##
## LEF for PtnCells ;
## created by Innovus v17.13-s098_1 on Sat Dec  7 00:01:32 2019
##

VERSION 5.8 ;

BUSBITCHARS "[]" ;
DIVIDERCHAR "/" ;

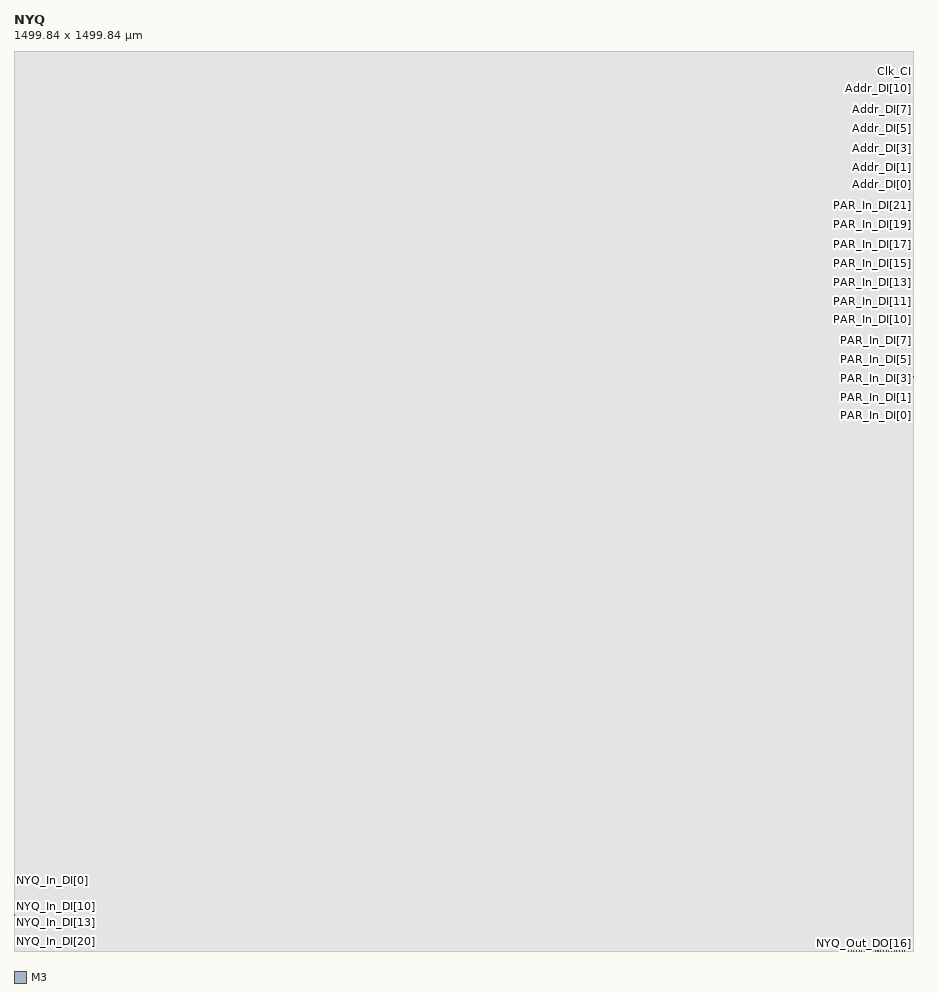
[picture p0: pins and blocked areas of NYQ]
MACRO NYQ
  CLASS BLOCK ;
  SIZE 1499.8400 BY 1499.8400 ;
  FOREIGN NYQ 0.0000 0.0000 ;
  ORIGIN 0 0 ;
  SYMMETRY X Y R90 ;
  PIN Clk_CI
    DIRECTION INPUT ;
    USE SIGNAL ;
    PORT
      LAYER M3 ;
        RECT 1499.6800 1452.5600 1499.8400 1452.7200 ;
    END
  END Clk_CI
  PIN Rst_RBI
    DIRECTION INPUT ;
    USE SIGNAL ;
    PORT
      LAYER M3 ;
        RECT 1499.6800 1468.5600 1499.8400 1468.7200 ;
    END
  END Rst_RBI
  PIN WrEn_SI
    DIRECTION INPUT ;
    USE SIGNAL ;
    PORT
      LAYER M3 ;
        RECT 1499.6800 1484.5600 1499.8400 1484.7200 ;
    END
  END WrEn_SI
  PIN Addr_DI[10]
    DIRECTION INPUT ;
    USE SIGNAL ;
    PORT
      LAYER M3 ;
        RECT 1499.6800 1436.5600 1499.8400 1436.7200 ;
    END
  END Addr_DI[10]
  PIN Addr_DI[9]
    DIRECTION INPUT ;
    USE SIGNAL ;
    PORT
      LAYER M3 ;
        RECT 1499.6800 1420.5600 1499.8400 1420.7200 ;
    END
  END Addr_DI[9]
  PIN Addr_DI[8]
    DIRECTION INPUT ;
    USE SIGNAL ;
    PORT
      LAYER M3 ;
        RECT 1499.6800 1404.5600 1499.8400 1404.7200 ;
    END
  END Addr_DI[8]
  PIN Addr_DI[7]
    DIRECTION INPUT ;
    USE SIGNAL ;
    PORT
      LAYER M3 ;
        RECT 1499.6800 1388.5600 1499.8400 1388.7200 ;
    END
  END Addr_DI[7]
  PIN Addr_DI[6]
    DIRECTION INPUT ;
    USE SIGNAL ;
    PORT
      LAYER M3 ;
        RECT 1499.6800 1372.5600 1499.8400 1372.7200 ;
    END
  END Addr_DI[6]
  PIN Addr_DI[5]
    DIRECTION INPUT ;
    USE SIGNAL ;
    PORT
      LAYER M3 ;
        RECT 1499.6800 1356.5600 1499.8400 1356.7200 ;
    END
  END Addr_DI[5]
  PIN Addr_DI[4]
    DIRECTION INPUT ;
    USE SIGNAL ;
    PORT
      LAYER M3 ;
        RECT 1499.6800 1340.5600 1499.8400 1340.7200 ;
    END
  END Addr_DI[4]
  PIN Addr_DI[3]
    DIRECTION INPUT ;
    USE SIGNAL ;
    PORT
      LAYER M3 ;
        RECT 1499.6800 1324.5600 1499.8400 1324.7200 ;
    END
  END Addr_DI[3]
  PIN Addr_DI[2]
    DIRECTION INPUT ;
    USE SIGNAL ;
    PORT
      LAYER M3 ;
        RECT 1499.6800 1308.5600 1499.8400 1308.7200 ;
    END
  END Addr_DI[2]
  PIN Addr_DI[1]
    DIRECTION INPUT ;
    USE SIGNAL ;
    PORT
      LAYER M3 ;
        RECT 1499.6800 1292.5600 1499.8400 1292.7200 ;
    END
  END Addr_DI[1]
  PIN Addr_DI[0]
    DIRECTION INPUT ;
    USE SIGNAL ;
    PORT
      LAYER M3 ;
        RECT 1499.6800 1276.5600 1499.8400 1276.7200 ;
    END
  END Addr_DI[0]
  PIN PAR_In_DI[23]
    DIRECTION INPUT ;
    USE SIGNAL ;
    PORT
      LAYER M3 ;
        RECT 1499.6800 1260.5600 1499.8400 1260.7200 ;
    END
  END PAR_In_DI[23]
  PIN PAR_In_DI[22]
    DIRECTION INPUT ;
    USE SIGNAL ;
    PORT
      LAYER M3 ;
        RECT 1499.6800 1244.5600 1499.8400 1244.7200 ;
    END
  END PAR_In_DI[22]
  PIN PAR_In_DI[21]
    DIRECTION INPUT ;
    USE SIGNAL ;
    PORT
      LAYER M3 ;
        RECT 1499.6800 1228.5600 1499.8400 1228.7200 ;
    END
  END PAR_In_DI[21]
  PIN PAR_In_DI[20]
    DIRECTION INPUT ;
    USE SIGNAL ;
    PORT
      LAYER M3 ;
        RECT 1499.6800 1212.5600 1499.8400 1212.7200 ;
    END
  END PAR_In_DI[20]
  PIN PAR_In_DI[19]
    DIRECTION INPUT ;
    USE SIGNAL ;
    PORT
      LAYER M3 ;
        RECT 1499.6800 1196.5600 1499.8400 1196.7200 ;
    END
  END PAR_In_DI[19]
  PIN PAR_In_DI[18]
    DIRECTION INPUT ;
    USE SIGNAL ;
    PORT
      LAYER M3 ;
        RECT 1499.6800 1180.5600 1499.8400 1180.7200 ;
    END
  END PAR_In_DI[18]
  PIN PAR_In_DI[17]
    DIRECTION INPUT ;
    USE SIGNAL ;
    PORT
      LAYER M3 ;
        RECT 1499.6800 1164.5600 1499.8400 1164.7200 ;
    END
  END PAR_In_DI[17]
  PIN PAR_In_DI[16]
    DIRECTION INPUT ;
    USE SIGNAL ;
    PORT
      LAYER M3 ;
        RECT 1499.6800 1148.5600 1499.8400 1148.7200 ;
    END
  END PAR_In_DI[16]
  PIN PAR_In_DI[15]
    DIRECTION INPUT ;
    USE SIGNAL ;
    PORT
      LAYER M3 ;
        RECT 1499.6800 1132.5600 1499.8400 1132.7200 ;
    END
  END PAR_In_DI[15]
  PIN PAR_In_DI[14]
    DIRECTION INPUT ;
    USE SIGNAL ;
    PORT
      LAYER M3 ;
        RECT 1499.6800 1116.5600 1499.8400 1116.7200 ;
    END
  END PAR_In_DI[14]
  PIN PAR_In_DI[13]
    DIRECTION INPUT ;
    USE SIGNAL ;
    PORT
      LAYER M3 ;
        RECT 1499.6800 1100.5600 1499.8400 1100.7200 ;
    END
  END PAR_In_DI[13]
  PIN PAR_In_DI[12]
    DIRECTION INPUT ;
    USE SIGNAL ;
    PORT
      LAYER M3 ;
        RECT 1499.6800 1084.5600 1499.8400 1084.7200 ;
    END
  END PAR_In_DI[12]
  PIN PAR_In_DI[11]
    DIRECTION INPUT ;
    USE SIGNAL ;
    PORT
      LAYER M3 ;
        RECT 1499.6800 1068.5600 1499.8400 1068.7200 ;
    END
  END PAR_In_DI[11]
  PIN PAR_In_DI[10]
    DIRECTION INPUT ;
    USE SIGNAL ;
    PORT
      LAYER M3 ;
        RECT 1499.6800 1052.5600 1499.8400 1052.7200 ;
    END
  END PAR_In_DI[10]
  PIN PAR_In_DI[9]
    DIRECTION INPUT ;
    USE SIGNAL ;
    PORT
      LAYER M3 ;
        RECT 1499.6800 1036.5600 1499.8400 1036.7200 ;
    END
  END PAR_In_DI[9]
  PIN PAR_In_DI[8]
    DIRECTION INPUT ;
    USE SIGNAL ;
    PORT
      LAYER M3 ;
        RECT 1499.6800 1020.5600 1499.8400 1020.7200 ;
    END
  END PAR_In_DI[8]
  PIN PAR_In_DI[7]
    DIRECTION INPUT ;
    USE SIGNAL ;
    PORT
      LAYER M3 ;
        RECT 1499.6800 1004.5600 1499.8400 1004.7200 ;
    END
  END PAR_In_DI[7]
  PIN PAR_In_DI[6]
    DIRECTION INPUT ;
    USE SIGNAL ;
    PORT
      LAYER M3 ;
        RECT 1499.6800 988.5600 1499.8400 988.7200 ;
    END
  END PAR_In_DI[6]
  PIN PAR_In_DI[5]
    DIRECTION INPUT ;
    USE SIGNAL ;
    PORT
      LAYER M3 ;
        RECT 1499.6800 972.5600 1499.8400 972.7200 ;
    END
  END PAR_In_DI[5]
  PIN PAR_In_DI[4]
    DIRECTION INPUT ;
    USE SIGNAL ;
    PORT
      LAYER M3 ;
        RECT 1499.6800 956.5600 1499.8400 956.7200 ;
    END
  END PAR_In_DI[4]
  PIN PAR_In_DI[3]
    DIRECTION INPUT ;
    USE SIGNAL ;
    PORT
      LAYER M3 ;
        RECT 1499.6800 940.5600 1499.8400 940.7200 ;
    END
  END PAR_In_DI[3]
  PIN PAR_In_DI[2]
    DIRECTION INPUT ;
    USE SIGNAL ;
    PORT
      LAYER M3 ;
        RECT 1499.6800 924.5600 1499.8400 924.7200 ;
    END
  END PAR_In_DI[2]
  PIN PAR_In_DI[1]
    DIRECTION INPUT ;
    USE SIGNAL ;
    PORT
      LAYER M3 ;
        RECT 1499.6800 908.5600 1499.8400 908.7200 ;
    END
  END PAR_In_DI[1]
  PIN PAR_In_DI[0]
    DIRECTION INPUT ;
    USE SIGNAL ;
    PORT
      LAYER M3 ;
        RECT 1499.6800 892.5600 1499.8400 892.7200 ;
    END
  END PAR_In_DI[0]
  PIN NYQ_In_DI[23]
    DIRECTION INPUT ;
    USE SIGNAL ;
    PORT
      LAYER M3 ;
        RECT 0.0000 15.1200 0.1600 15.2800 ;
    END
  END NYQ_In_DI[23]
  PIN NYQ_In_DI[22]
    DIRECTION INPUT ;
    USE SIGNAL ;
    PORT
      LAYER M3 ;
        RECT 0.0000 19.6000 0.1600 19.7600 ;
    END
  END NYQ_In_DI[22]
  PIN NYQ_In_DI[21]
    DIRECTION INPUT ;
    USE SIGNAL ;
    PORT
      LAYER M3 ;
        RECT 0.0000 24.0800 0.1600 24.2400 ;
    END
  END NYQ_In_DI[21]
  PIN NYQ_In_DI[20]
    DIRECTION INPUT ;
    USE SIGNAL ;
    PORT
      LAYER M3 ;
        RECT 0.0000 28.5600 0.1600 28.7200 ;
    END
  END NYQ_In_DI[20]
  PIN NYQ_In_DI[19]
    DIRECTION INPUT ;
    USE SIGNAL ;
    PORT
      LAYER M3 ;
        RECT 0.0000 33.0400 0.1600 33.2000 ;
    END
  END NYQ_In_DI[19]
  PIN NYQ_In_DI[18]
    DIRECTION INPUT ;
    USE SIGNAL ;
    PORT
      LAYER M3 ;
        RECT 0.0000 37.5200 0.1600 37.6800 ;
    END
  END NYQ_In_DI[18]
  PIN NYQ_In_DI[17]
    DIRECTION INPUT ;
    USE SIGNAL ;
    PORT
      LAYER M3 ;
        RECT 0.0000 42.0000 0.1600 42.1600 ;
    END
  END NYQ_In_DI[17]
  PIN NYQ_In_DI[16]
    DIRECTION INPUT ;
    USE SIGNAL ;
    PORT
      LAYER M3 ;
        RECT 0.0000 46.4800 0.1600 46.6400 ;
    END
  END NYQ_In_DI[16]
  PIN NYQ_In_DI[15]
    DIRECTION INPUT ;
    USE SIGNAL ;
    PORT
      LAYER M3 ;
        RECT 0.0000 50.9600 0.1600 51.1200 ;
    END
  END NYQ_In_DI[15]
  PIN NYQ_In_DI[14]
    DIRECTION INPUT ;
    USE SIGNAL ;
    PORT
      LAYER M3 ;
        RECT 0.0000 55.4400 0.1600 55.6000 ;
    END
  END NYQ_In_DI[14]
  PIN NYQ_In_DI[13]
    DIRECTION INPUT ;
    USE SIGNAL ;
    PORT
      LAYER M3 ;
        RECT 0.0000 59.9200 0.1600 60.0800 ;
    END
  END NYQ_In_DI[13]
  PIN NYQ_In_DI[12]
    DIRECTION INPUT ;
    USE SIGNAL ;
    PORT
      LAYER M3 ;
        RECT 0.0000 64.4000 0.1600 64.5600 ;
    END
  END NYQ_In_DI[12]
  PIN NYQ_In_DI[11]
    DIRECTION INPUT ;
    USE SIGNAL ;
    PORT
      LAYER M3 ;
        RECT 0.0000 68.8800 0.1600 69.0400 ;
    END
  END NYQ_In_DI[11]
  PIN NYQ_In_DI[10]
    DIRECTION INPUT ;
    USE SIGNAL ;
    PORT
      LAYER M3 ;
        RECT 0.0000 73.3600 0.1600 73.5200 ;
    END
  END NYQ_In_DI[10]
  PIN NYQ_In_DI[9]
    DIRECTION INPUT ;
    USE SIGNAL ;
    PORT
      LAYER M3 ;
        RECT 0.0000 77.8400 0.1600 78.0000 ;
    END
  END NYQ_In_DI[9]
  PIN NYQ_In_DI[8]
    DIRECTION INPUT ;
    USE SIGNAL ;
    PORT
      LAYER M3 ;
        RECT 0.0000 82.3200 0.1600 82.4800 ;
    END
  END NYQ_In_DI[8]
  PIN NYQ_In_DI[7]
    DIRECTION INPUT ;
    USE SIGNAL ;
    PORT
      LAYER M3 ;
        RECT 0.0000 86.8000 0.1600 86.9600 ;
    END
  END NYQ_In_DI[7]
  PIN NYQ_In_DI[6]
    DIRECTION INPUT ;
    USE SIGNAL ;
    PORT
      LAYER M3 ;
        RECT 0.0000 91.2800 0.1600 91.4400 ;
    END
  END NYQ_In_DI[6]
  PIN NYQ_In_DI[5]
    DIRECTION INPUT ;
    USE SIGNAL ;
    PORT
      LAYER M3 ;
        RECT 0.0000 95.7600 0.1600 95.9200 ;
    END
  END NYQ_In_DI[5]
  PIN NYQ_In_DI[4]
    DIRECTION INPUT ;
    USE SIGNAL ;
    PORT
      LAYER M3 ;
        RECT 0.0000 100.2400 0.1600 100.4000 ;
    END
  END NYQ_In_DI[4]
  PIN NYQ_In_DI[3]
    DIRECTION INPUT ;
    USE SIGNAL ;
    PORT
      LAYER M3 ;
        RECT 0.0000 104.7200 0.1600 104.8800 ;
    END
  END NYQ_In_DI[3]
  PIN NYQ_In_DI[2]
    DIRECTION INPUT ;
    USE SIGNAL ;
    PORT
      LAYER M3 ;
        RECT 0.0000 109.2000 0.1600 109.3600 ;
    END
  END NYQ_In_DI[2]
  PIN NYQ_In_DI[1]
    DIRECTION INPUT ;
    USE SIGNAL ;
    PORT
      LAYER M3 ;
        RECT 0.0000 113.6800 0.1600 113.8400 ;
    END
  END NYQ_In_DI[1]
  PIN NYQ_In_DI[0]
    DIRECTION INPUT ;
    USE SIGNAL ;
    PORT
      LAYER M3 ;
        RECT 0.0000 118.1600 0.1600 118.3200 ;
    END
  END NYQ_In_DI[0]
  PIN NYQ_Out_DO[23]
    DIRECTION OUTPUT ;
    USE SIGNAL ;
    PORT
      LAYER M3 ;
        RECT 1484.5600 0.0000 1484.7200 0.1600 ;
    END
  END NYQ_Out_DO[23]
  PIN NYQ_Out_DO[22]
    DIRECTION OUTPUT ;
    USE SIGNAL ;
    PORT
      LAYER M3 ;
        RECT 1480.0800 0.0000 1480.2400 0.1600 ;
    END
  END NYQ_Out_DO[22]
  PIN NYQ_Out_DO[21]
    DIRECTION OUTPUT ;
    USE SIGNAL ;
    PORT
      LAYER M3 ;
        RECT 1475.6000 0.0000 1475.7600 0.1600 ;
    END
  END NYQ_Out_DO[21]
  PIN NYQ_Out_DO[20]
    DIRECTION OUTPUT ;
    USE SIGNAL ;
    PORT
      LAYER M3 ;
        RECT 1471.1200 0.0000 1471.2800 0.1600 ;
    END
  END NYQ_Out_DO[20]
  PIN NYQ_Out_DO[19]
    DIRECTION OUTPUT ;
    USE SIGNAL ;
    PORT
      LAYER M3 ;
        RECT 1466.6400 0.0000 1466.8000 0.1600 ;
    END
  END NYQ_Out_DO[19]
  PIN NYQ_Out_DO[18]
    DIRECTION OUTPUT ;
    USE SIGNAL ;
    PORT
      LAYER M3 ;
        RECT 1462.1600 0.0000 1462.3200 0.1600 ;
    END
  END NYQ_Out_DO[18]
  PIN NYQ_Out_DO[17]
    DIRECTION OUTPUT ;
    USE SIGNAL ;
    PORT
      LAYER M3 ;
        RECT 1457.6800 0.0000 1457.8400 0.1600 ;
    END
  END NYQ_Out_DO[17]
  PIN NYQ_Out_DO[16]
    DIRECTION OUTPUT ;
    USE SIGNAL ;
    PORT
      LAYER M3 ;
        RECT 1453.2000 0.0000 1453.3600 0.1600 ;
    END
  END NYQ_Out_DO[16]
  PIN NYQ_Out_DO[15]
    DIRECTION OUTPUT ;
    USE SIGNAL ;
    PORT
      LAYER M3 ;
        RECT 1448.7200 0.0000 1448.8800 0.1600 ;
    END
  END NYQ_Out_DO[15]
  PIN NYQ_Out_DO[14]
    DIRECTION OUTPUT ;
    USE SIGNAL ;
    PORT
      LAYER M3 ;
        RECT 1444.2400 0.0000 1444.4000 0.1600 ;
    END
  END NYQ_Out_DO[14]
  PIN NYQ_Out_DO[13]
    DIRECTION OUTPUT ;
    USE SIGNAL ;
    PORT
      LAYER M3 ;
        RECT 1439.7600 0.0000 1439.9200 0.1600 ;
    END
  END NYQ_Out_DO[13]
  PIN NYQ_Out_DO[12]
    DIRECTION OUTPUT ;
    USE SIGNAL ;
    PORT
      LAYER M3 ;
        RECT 1435.2800 0.0000 1435.4400 0.1600 ;
    END
  END NYQ_Out_DO[12]
  PIN NYQ_Out_DO[11]
    DIRECTION OUTPUT ;
    USE SIGNAL ;
    PORT
      LAYER M3 ;
        RECT 1430.8000 0.0000 1430.9600 0.1600 ;
    END
  END NYQ_Out_DO[11]
  PIN NYQ_Out_DO[10]
    DIRECTION OUTPUT ;
    USE SIGNAL ;
    PORT
      LAYER M3 ;
        RECT 1426.3200 0.0000 1426.4800 0.1600 ;
    END
  END NYQ_Out_DO[10]
  PIN NYQ_Out_DO[9]
    DIRECTION OUTPUT ;
    USE SIGNAL ;
    PORT
      LAYER M3 ;
        RECT 1421.8400 0.0000 1422.0000 0.1600 ;
    END
  END NYQ_Out_DO[9]
  PIN NYQ_Out_DO[8]
    DIRECTION OUTPUT ;
    USE SIGNAL ;
    PORT
      LAYER M3 ;
        RECT 1417.3600 0.0000 1417.5200 0.1600 ;
    END
  END NYQ_Out_DO[8]
  PIN NYQ_Out_DO[7]
    DIRECTION OUTPUT ;
    USE SIGNAL ;
    PORT
      LAYER M3 ;
        RECT 1412.8800 0.0000 1413.0400 0.1600 ;
    END
  END NYQ_Out_DO[7]
  PIN NYQ_Out_DO[6]
    DIRECTION OUTPUT ;
    USE SIGNAL ;
    PORT
      LAYER M3 ;
        RECT 1408.4000 0.0000 1408.5600 0.1600 ;
    END
  END NYQ_Out_DO[6]
  PIN NYQ_Out_DO[5]
    DIRECTION OUTPUT ;
    USE SIGNAL ;
    PORT
      LAYER M3 ;
        RECT 1403.9200 0.0000 1404.0800 0.1600 ;
    END
  END NYQ_Out_DO[5]
  PIN NYQ_Out_DO[4]
    DIRECTION OUTPUT ;
    USE SIGNAL ;
    PORT
      LAYER M3 ;
        RECT 1399.4400 0.0000 1399.6000 0.1600 ;
    END
  END NYQ_Out_DO[4]
  PIN NYQ_Out_DO[3]
    DIRECTION OUTPUT ;
    USE SIGNAL ;
    PORT
      LAYER M3 ;
        RECT 1394.9600 0.0000 1395.1200 0.1600 ;
    END
  END NYQ_Out_DO[3]
  PIN NYQ_Out_DO[2]
    DIRECTION OUTPUT ;
    USE SIGNAL ;
    PORT
      LAYER M3 ;
        RECT 1390.4800 0.0000 1390.6400 0.1600 ;
    END
  END NYQ_Out_DO[2]
  PIN NYQ_Out_DO[1]
    DIRECTION OUTPUT ;
    USE SIGNAL ;
    PORT
      LAYER M3 ;
        RECT 1386.0000 0.0000 1386.1600 0.1600 ;
    END
  END NYQ_Out_DO[1]
  PIN NYQ_Out_DO[0]
    DIRECTION OUTPUT ;
    USE SIGNAL ;
    PORT
      LAYER M3 ;
        RECT 1381.5200 0.0000 1381.6800 0.1600 ;
    END
  END NYQ_Out_DO[0]
  PIN NYQ_Valid_DO
    DIRECTION OUTPUT ;
    USE SIGNAL ;
    PORT
      LAYER M3 ;
        RECT 1484.5600 1499.6800 1484.7200 1499.8400 ;
    END
  END NYQ_Valid_DO
  OBS
    LAYER M1 ;
      RECT 0.0000 0.0000 1499.8400 1499.8400 ;
    LAYER M2 ;
      RECT 0.0000 0.0000 1499.8400 1499.8400 ;
    LAYER M3 ;
      RECT 1484.8800 1499.5200 1499.8400 1499.8400 ;
      RECT 0.0000 1499.5200 1484.4000 1499.8400 ;
      RECT 0.0000 1484.8800 1499.8400 1499.5200 ;
      RECT 0.0000 1484.4000 1499.5200 1484.8800 ;
      RECT 0.0000 1468.8800 1499.8400 1484.4000 ;
      RECT 0.0000 1468.4000 1499.5200 1468.8800 ;
      RECT 0.0000 1452.8800 1499.8400 1468.4000 ;
      RECT 0.0000 1452.4000 1499.5200 1452.8800 ;
      RECT 0.0000 1436.8800 1499.8400 1452.4000 ;
      RECT 0.0000 1436.4000 1499.5200 1436.8800 ;
      RECT 0.0000 1420.8800 1499.8400 1436.4000 ;
      RECT 0.0000 1420.4000 1499.5200 1420.8800 ;
      RECT 0.0000 1404.8800 1499.8400 1420.4000 ;
      RECT 0.0000 1404.4000 1499.5200 1404.8800 ;
      RECT 0.0000 1388.8800 1499.8400 1404.4000 ;
      RECT 0.0000 1388.4000 1499.5200 1388.8800 ;
      RECT 0.0000 1372.8800 1499.8400 1388.4000 ;
      RECT 0.0000 1372.4000 1499.5200 1372.8800 ;
      RECT 0.0000 1356.8800 1499.8400 1372.4000 ;
      RECT 0.0000 1356.4000 1499.5200 1356.8800 ;
      RECT 0.0000 1340.8800 1499.8400 1356.4000 ;
      RECT 0.0000 1340.4000 1499.5200 1340.8800 ;
      RECT 0.0000 1324.8800 1499.8400 1340.4000 ;
      RECT 0.0000 1324.4000 1499.5200 1324.8800 ;
      RECT 0.0000 1308.8800 1499.8400 1324.4000 ;
      RECT 0.0000 1308.4000 1499.5200 1308.8800 ;
      RECT 0.0000 1292.8800 1499.8400 1308.4000 ;
      RECT 0.0000 1292.4000 1499.5200 1292.8800 ;
      RECT 0.0000 1276.8800 1499.8400 1292.4000 ;
      RECT 0.0000 1276.4000 1499.5200 1276.8800 ;
      RECT 0.0000 1260.8800 1499.8400 1276.4000 ;
      RECT 0.0000 1260.4000 1499.5200 1260.8800 ;
      RECT 0.0000 1244.8800 1499.8400 1260.4000 ;
      RECT 0.0000 1244.4000 1499.5200 1244.8800 ;
      RECT 0.0000 1228.8800 1499.8400 1244.4000 ;
      RECT 0.0000 1228.4000 1499.5200 1228.8800 ;
      RECT 0.0000 1212.8800 1499.8400 1228.4000 ;
      RECT 0.0000 1212.4000 1499.5200 1212.8800 ;
      RECT 0.0000 1196.8800 1499.8400 1212.4000 ;
      RECT 0.0000 1196.4000 1499.5200 1196.8800 ;
      RECT 0.0000 1180.8800 1499.8400 1196.4000 ;
      RECT 0.0000 1180.4000 1499.5200 1180.8800 ;
      RECT 0.0000 1164.8800 1499.8400 1180.4000 ;
      RECT 0.0000 1164.4000 1499.5200 1164.8800 ;
      RECT 0.0000 1148.8800 1499.8400 1164.4000 ;
      RECT 0.0000 1148.4000 1499.5200 1148.8800 ;
      RECT 0.0000 1132.8800 1499.8400 1148.4000 ;
      RECT 0.0000 1132.4000 1499.5200 1132.8800 ;
      RECT 0.0000 1116.8800 1499.8400 1132.4000 ;
      RECT 0.0000 1116.4000 1499.5200 1116.8800 ;
      RECT 0.0000 1100.8800 1499.8400 1116.4000 ;
      RECT 0.0000 1100.4000 1499.5200 1100.8800 ;
      RECT 0.0000 1084.8800 1499.8400 1100.4000 ;
      RECT 0.0000 1084.4000 1499.5200 1084.8800 ;
      RECT 0.0000 1068.8800 1499.8400 1084.4000 ;
      RECT 0.0000 1068.4000 1499.5200 1068.8800 ;
      RECT 0.0000 1052.8800 1499.8400 1068.4000 ;
      RECT 0.0000 1052.4000 1499.5200 1052.8800 ;
      RECT 0.0000 1036.8800 1499.8400 1052.4000 ;
      RECT 0.0000 1036.4000 1499.5200 1036.8800 ;
      RECT 0.0000 1020.8800 1499.8400 1036.4000 ;
      RECT 0.0000 1020.4000 1499.5200 1020.8800 ;
      RECT 0.0000 1004.8800 1499.8400 1020.4000 ;
      RECT 0.0000 1004.4000 1499.5200 1004.8800 ;
      RECT 0.0000 988.8800 1499.8400 1004.4000 ;
      RECT 0.0000 988.4000 1499.5200 988.8800 ;
      RECT 0.0000 972.8800 1499.8400 988.4000 ;
      RECT 0.0000 972.4000 1499.5200 972.8800 ;
      RECT 0.0000 956.8800 1499.8400 972.4000 ;
      RECT 0.0000 956.4000 1499.5200 956.8800 ;
      RECT 0.0000 940.8800 1499.8400 956.4000 ;
      RECT 0.0000 940.4000 1499.5200 940.8800 ;
      RECT 0.0000 924.8800 1499.8400 940.4000 ;
      RECT 0.0000 924.4000 1499.5200 924.8800 ;
      RECT 0.0000 908.8800 1499.8400 924.4000 ;
      RECT 0.0000 908.4000 1499.5200 908.8800 ;
      RECT 0.0000 892.8800 1499.8400 908.4000 ;
      RECT 0.0000 892.4000 1499.5200 892.8800 ;
      RECT 0.0000 118.4800 1499.8400 892.4000 ;
      RECT 0.3200 118.0000 1499.8400 118.4800 ;
      RECT 0.0000 114.0000 1499.8400 118.0000 ;
      RECT 0.3200 113.5200 1499.8400 114.0000 ;
      RECT 0.0000 109.5200 1499.8400 113.5200 ;
      RECT 0.3200 109.0400 1499.8400 109.5200 ;
      RECT 0.0000 105.0400 1499.8400 109.0400 ;
      RECT 0.3200 104.5600 1499.8400 105.0400 ;
      RECT 0.0000 100.5600 1499.8400 104.5600 ;
      RECT 0.3200 100.0800 1499.8400 100.5600 ;
      RECT 0.0000 96.0800 1499.8400 100.0800 ;
      RECT 0.3200 95.6000 1499.8400 96.0800 ;
      RECT 0.0000 91.6000 1499.8400 95.6000 ;
      RECT 0.3200 91.1200 1499.8400 91.6000 ;
      RECT 0.0000 87.1200 1499.8400 91.1200 ;
      RECT 0.3200 86.6400 1499.8400 87.1200 ;
      RECT 0.0000 82.6400 1499.8400 86.6400 ;
      RECT 0.3200 82.1600 1499.8400 82.6400 ;
      RECT 0.0000 78.1600 1499.8400 82.1600 ;
      RECT 0.3200 77.6800 1499.8400 78.1600 ;
      RECT 0.0000 73.6800 1499.8400 77.6800 ;
      RECT 0.3200 73.2000 1499.8400 73.6800 ;
      RECT 0.0000 69.2000 1499.8400 73.2000 ;
      RECT 0.3200 68.7200 1499.8400 69.2000 ;
      RECT 0.0000 64.7200 1499.8400 68.7200 ;
      RECT 0.3200 64.2400 1499.8400 64.7200 ;
      RECT 0.0000 60.2400 1499.8400 64.2400 ;
      RECT 0.3200 59.7600 1499.8400 60.2400 ;
      RECT 0.0000 55.7600 1499.8400 59.7600 ;
      RECT 0.3200 55.2800 1499.8400 55.7600 ;
      RECT 0.0000 51.2800 1499.8400 55.2800 ;
      RECT 0.3200 50.8000 1499.8400 51.2800 ;
      RECT 0.0000 46.8000 1499.8400 50.8000 ;
      RECT 0.3200 46.3200 1499.8400 46.8000 ;
      RECT 0.0000 42.3200 1499.8400 46.3200 ;
      RECT 0.3200 41.8400 1499.8400 42.3200 ;
      RECT 0.0000 37.8400 1499.8400 41.8400 ;
      RECT 0.3200 37.3600 1499.8400 37.8400 ;
      RECT 0.0000 33.3600 1499.8400 37.3600 ;
      RECT 0.3200 32.8800 1499.8400 33.3600 ;
      RECT 0.0000 28.8800 1499.8400 32.8800 ;
      RECT 0.3200 28.4000 1499.8400 28.8800 ;
      RECT 0.0000 24.4000 1499.8400 28.4000 ;
      RECT 0.3200 23.9200 1499.8400 24.4000 ;
      RECT 0.0000 19.9200 1499.8400 23.9200 ;
      RECT 0.3200 19.4400 1499.8400 19.9200 ;
      RECT 0.0000 15.4400 1499.8400 19.4400 ;
      RECT 0.3200 14.9600 1499.8400 15.4400 ;
      RECT 0.0000 0.3200 1499.8400 14.9600 ;
      RECT 1484.8800 0.0000 1499.8400 0.3200 ;
      RECT 1480.4000 0.0000 1484.4000 0.3200 ;
      RECT 1475.9200 0.0000 1479.9200 0.3200 ;
      RECT 1471.4400 0.0000 1475.4400 0.3200 ;
      RECT 1466.9600 0.0000 1470.9600 0.3200 ;
      RECT 1462.4800 0.0000 1466.4800 0.3200 ;
      RECT 1458.0000 0.0000 1462.0000 0.3200 ;
      RECT 1453.5200 0.0000 1457.5200 0.3200 ;
      RECT 1449.0400 0.0000 1453.0400 0.3200 ;
      RECT 1444.5600 0.0000 1448.5600 0.3200 ;
      RECT 1440.0800 0.0000 1444.0800 0.3200 ;
      RECT 1435.6000 0.0000 1439.6000 0.3200 ;
      RECT 1431.1200 0.0000 1435.1200 0.3200 ;
      RECT 1426.6400 0.0000 1430.6400 0.3200 ;
      RECT 1422.1600 0.0000 1426.1600 0.3200 ;
      RECT 1417.6800 0.0000 1421.6800 0.3200 ;
      RECT 1413.2000 0.0000 1417.2000 0.3200 ;
      RECT 1408.7200 0.0000 1412.7200 0.3200 ;
      RECT 1404.2400 0.0000 1408.2400 0.3200 ;
      RECT 1399.7600 0.0000 1403.7600 0.3200 ;
      RECT 1395.2800 0.0000 1399.2800 0.3200 ;
      RECT 1390.8000 0.0000 1394.8000 0.3200 ;
      RECT 1386.3200 0.0000 1390.3200 0.3200 ;
      RECT 1381.8400 0.0000 1385.8400 0.3200 ;
      RECT 0.0000 0.0000 1381.3600 0.3200 ;
    LAYER M4 ;
      RECT 0.0000 0.0000 1499.8400 1499.8400 ;
    LAYER M5 ;
      RECT 0.0000 0.0000 1499.8400 1499.8400 ;
    LAYER M6 ;
      RECT 0.0000 0.0000 1499.8400 1499.8400 ;
    LAYER M7 ;
      RECT 0.0000 0.0000 1499.8400 1499.8400 ;
    LAYER M8 ;
      RECT 0.0000 0.0000 1499.8400 1499.8400 ;
    LAYER M9 ;
      RECT 0.0000 0.0000 1499.8400 1499.8400 ;
  END
END NYQ

END LIBRARY
